VERSION 5.7 ;
BUSBITCHARS "[]" ;
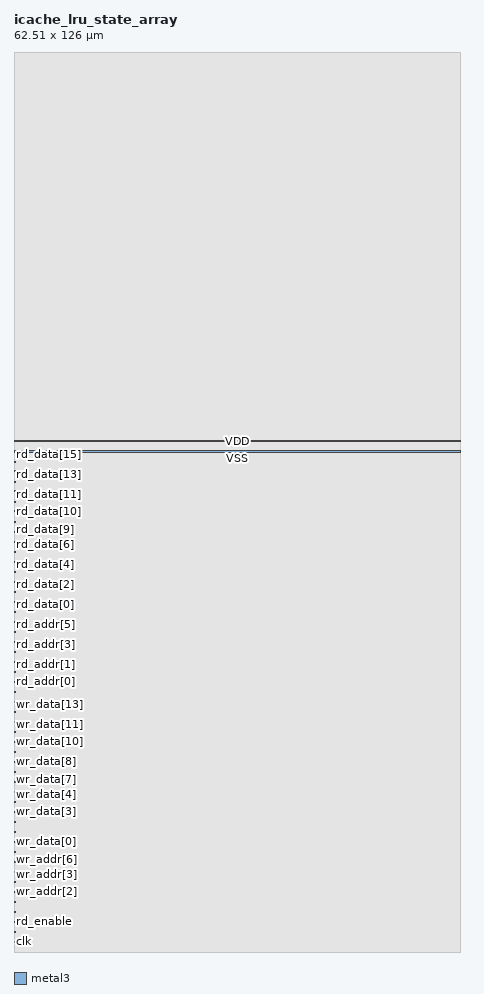
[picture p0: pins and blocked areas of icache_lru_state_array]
MACRO icache_lru_state_array
  FOREIGN icache_lru_state_array 0 0 ;
  SYMMETRY X Y R90 ;
  SIZE 62.510 BY 126.000 ;
  CLASS BLOCK ;
  PIN clk
    DIRECTION INPUT ;
    USE SIGNAL ;
    SHAPE ABUTMENT ;
    PORT
      LAYER metal3 ;
      RECT 0.000 1.400 0.140 1.540 ;
    END
  END clk
  PIN wr_enable
    DIRECTION INPUT ;
    USE SIGNAL ;
    SHAPE ABUTMENT ;
    PORT
      LAYER metal3 ;
      RECT 0.000 2.800 0.140 2.940 ;
    END
  END wr_enable
  PIN rd_enable
    DIRECTION INPUT ;
    USE SIGNAL ;
    SHAPE ABUTMENT ;
    PORT
      LAYER metal3 ;
      RECT 0.000 4.200 0.140 4.340 ;
    END
  END rd_enable
  PIN wr_addr[0]
    DIRECTION INPUT ;
    USE SIGNAL ;
    SHAPE ABUTMENT ;
    PORT
      LAYER metal3 ;
      RECT 0.000 5.600 0.140 5.740 ;
    END
  END wr_addr[0]
  PIN wr_addr[1]
    DIRECTION INPUT ;
    USE SIGNAL ;
    SHAPE ABUTMENT ;
    PORT
      LAYER metal3 ;
      RECT 0.000 7.000 0.140 7.140 ;
    END
  END wr_addr[1]
  PIN wr_addr[2]
    DIRECTION INPUT ;
    USE SIGNAL ;
    SHAPE ABUTMENT ;
    PORT
      LAYER metal3 ;
      RECT 0.000 8.400 0.140 8.540 ;
    END
  END wr_addr[2]
  PIN wr_addr[3]
    DIRECTION INPUT ;
    USE SIGNAL ;
    SHAPE ABUTMENT ;
    PORT
      LAYER metal3 ;
      RECT 0.000 9.800 0.140 9.940 ;
    END
  END wr_addr[3]
  PIN wr_addr[4]
    DIRECTION INPUT ;
    USE SIGNAL ;
    SHAPE ABUTMENT ;
    PORT
      LAYER metal3 ;
      RECT 0.000 11.200 0.140 11.340 ;
    END
  END wr_addr[4]
  PIN wr_addr[5]
    DIRECTION INPUT ;
    USE SIGNAL ;
    SHAPE ABUTMENT ;
    PORT
      LAYER metal3 ;
      RECT 0.000 12.600 0.140 12.740 ;
    END
  END wr_addr[5]
  PIN wr_addr[6]
    DIRECTION INPUT ;
    USE SIGNAL ;
    SHAPE ABUTMENT ;
    PORT
      LAYER metal3 ;
      RECT 0.000 14.000 0.140 14.140 ;
    END
  END wr_addr[6]
  PIN wr_data[0]
    DIRECTION INPUT ;
    USE SIGNAL ;
    SHAPE ABUTMENT ;
    PORT
      LAYER metal3 ;
      RECT 0.000 15.400 0.140 15.540 ;
    END
  END wr_data[0]
  PIN wr_data[1]
    DIRECTION INPUT ;
    USE SIGNAL ;
    SHAPE ABUTMENT ;
    PORT
      LAYER metal3 ;
      RECT 0.000 16.800 0.140 16.940 ;
    END
  END wr_data[1]
  PIN wr_data[2]
    DIRECTION INPUT ;
    USE SIGNAL ;
    SHAPE ABUTMENT ;
    PORT
      LAYER metal3 ;
      RECT 0.000 18.200 0.140 18.340 ;
    END
  END wr_data[2]
  PIN wr_data[3]
    DIRECTION INPUT ;
    USE SIGNAL ;
    SHAPE ABUTMENT ;
    PORT
      LAYER metal3 ;
      RECT 0.000 19.600 0.140 19.740 ;
    END
  END wr_data[3]
  PIN wr_data[4]
    DIRECTION INPUT ;
    USE SIGNAL ;
    SHAPE ABUTMENT ;
    PORT
      LAYER metal3 ;
      RECT 0.000 21.000 0.140 21.140 ;
    END
  END wr_data[4]
  PIN wr_data[5]
    DIRECTION INPUT ;
    USE SIGNAL ;
    SHAPE ABUTMENT ;
    PORT
      LAYER metal3 ;
      RECT 0.000 22.400 0.140 22.540 ;
    END
  END wr_data[5]
  PIN wr_data[6]
    DIRECTION INPUT ;
    USE SIGNAL ;
    SHAPE ABUTMENT ;
    PORT
      LAYER metal3 ;
      RECT 0.000 23.800 0.140 23.940 ;
    END
  END wr_data[6]
  PIN wr_data[7]
    DIRECTION INPUT ;
    USE SIGNAL ;
    SHAPE ABUTMENT ;
    PORT
      LAYER metal3 ;
      RECT 0.000 25.200 0.140 25.340 ;
    END
  END wr_data[7]
  PIN wr_data[8]
    DIRECTION INPUT ;
    USE SIGNAL ;
    SHAPE ABUTMENT ;
    PORT
      LAYER metal3 ;
      RECT 0.000 26.600 0.140 26.740 ;
    END
  END wr_data[8]
  PIN wr_data[9]
    DIRECTION INPUT ;
    USE SIGNAL ;
    SHAPE ABUTMENT ;
    PORT
      LAYER metal3 ;
      RECT 0.000 28.000 0.140 28.140 ;
    END
  END wr_data[9]
  PIN wr_data[10]
    DIRECTION INPUT ;
    USE SIGNAL ;
    SHAPE ABUTMENT ;
    PORT
      LAYER metal3 ;
      RECT 0.000 29.400 0.140 29.540 ;
    END
  END wr_data[10]
  PIN wr_data[11]
    DIRECTION INPUT ;
    USE SIGNAL ;
    SHAPE ABUTMENT ;
    PORT
      LAYER metal3 ;
      RECT 0.000 30.800 0.140 30.940 ;
    END
  END wr_data[11]
  PIN wr_data[12]
    DIRECTION INPUT ;
    USE SIGNAL ;
    SHAPE ABUTMENT ;
    PORT
      LAYER metal3 ;
      RECT 0.000 32.200 0.140 32.340 ;
    END
  END wr_data[12]
  PIN wr_data[13]
    DIRECTION INPUT ;
    USE SIGNAL ;
    SHAPE ABUTMENT ;
    PORT
      LAYER metal3 ;
      RECT 0.000 33.600 0.140 33.740 ;
    END
  END wr_data[13]
  PIN wr_data[14]
    DIRECTION INPUT ;
    USE SIGNAL ;
    SHAPE ABUTMENT ;
    PORT
      LAYER metal3 ;
      RECT 0.000 35.000 0.140 35.140 ;
    END
  END wr_data[14]
  PIN wr_data[15]
    DIRECTION INPUT ;
    USE SIGNAL ;
    SHAPE ABUTMENT ;
    PORT
      LAYER metal3 ;
      RECT 0.000 36.400 0.140 36.540 ;
    END
  END wr_data[15]
  PIN rd_addr[0]
    DIRECTION INPUT ;
    USE SIGNAL ;
    SHAPE ABUTMENT ;
    PORT
      LAYER metal3 ;
      RECT 0.000 37.800 0.140 37.940 ;
    END
  END rd_addr[0]
  PIN rd_addr[1]
    DIRECTION INPUT ;
    USE SIGNAL ;
    SHAPE ABUTMENT ;
    PORT
      LAYER metal3 ;
      RECT 0.000 39.200 0.140 39.340 ;
    END
  END rd_addr[1]
  PIN rd_addr[2]
    DIRECTION INPUT ;
    USE SIGNAL ;
    SHAPE ABUTMENT ;
    PORT
      LAYER metal3 ;
      RECT 0.000 40.600 0.140 40.740 ;
    END
  END rd_addr[2]
  PIN rd_addr[3]
    DIRECTION INPUT ;
    USE SIGNAL ;
    SHAPE ABUTMENT ;
    PORT
      LAYER metal3 ;
      RECT 0.000 42.000 0.140 42.140 ;
    END
  END rd_addr[3]
  PIN rd_addr[4]
    DIRECTION INPUT ;
    USE SIGNAL ;
    SHAPE ABUTMENT ;
    PORT
      LAYER metal3 ;
      RECT 0.000 43.400 0.140 43.540 ;
    END
  END rd_addr[4]
  PIN rd_addr[5]
    DIRECTION INPUT ;
    USE SIGNAL ;
    SHAPE ABUTMENT ;
    PORT
      LAYER metal3 ;
      RECT 0.000 44.800 0.140 44.940 ;
    END
  END rd_addr[5]
  PIN rd_addr[6]
    DIRECTION INPUT ;
    USE SIGNAL ;
    SHAPE ABUTMENT ;
    PORT
      LAYER metal3 ;
      RECT 0.000 46.200 0.140 46.340 ;
    END
  END rd_addr[6]
  PIN rd_data[0]
    DIRECTION OUTPUT ;
    USE SIGNAL ;
    SHAPE ABUTMENT ;
    PORT
      LAYER metal3 ;
      RECT 0.000 47.600 0.140 47.740 ;
    END
  END rd_data[0]
  PIN rd_data[1]
    DIRECTION OUTPUT ;
    USE SIGNAL ;
    SHAPE ABUTMENT ;
    PORT
      LAYER metal3 ;
      RECT 0.000 49.000 0.140 49.140 ;
    END
  END rd_data[1]
  PIN rd_data[2]
    DIRECTION OUTPUT ;
    USE SIGNAL ;
    SHAPE ABUTMENT ;
    PORT
      LAYER metal3 ;
      RECT 0.000 50.400 0.140 50.540 ;
    END
  END rd_data[2]
  PIN rd_data[3]
    DIRECTION OUTPUT ;
    USE SIGNAL ;
    SHAPE ABUTMENT ;
    PORT
      LAYER metal3 ;
      RECT 0.000 51.800 0.140 51.940 ;
    END
  END rd_data[3]
  PIN rd_data[4]
    DIRECTION OUTPUT ;
    USE SIGNAL ;
    SHAPE ABUTMENT ;
    PORT
      LAYER metal3 ;
      RECT 0.000 53.200 0.140 53.340 ;
    END
  END rd_data[4]
  PIN rd_data[5]
    DIRECTION OUTPUT ;
    USE SIGNAL ;
    SHAPE ABUTMENT ;
    PORT
      LAYER metal3 ;
      RECT 0.000 54.600 0.140 54.740 ;
    END
  END rd_data[5]
  PIN rd_data[6]
    DIRECTION OUTPUT ;
    USE SIGNAL ;
    SHAPE ABUTMENT ;
    PORT
      LAYER metal3 ;
      RECT 0.000 56.000 0.140 56.140 ;
    END
  END rd_data[6]
  PIN rd_data[7]
    DIRECTION OUTPUT ;
    USE SIGNAL ;
    SHAPE ABUTMENT ;
    PORT
      LAYER metal3 ;
      RECT 0.000 57.400 0.140 57.540 ;
    END
  END rd_data[7]
  PIN rd_data[8]
    DIRECTION OUTPUT ;
    USE SIGNAL ;
    SHAPE ABUTMENT ;
    PORT
      LAYER metal3 ;
      RECT 0.000 58.800 0.140 58.940 ;
    END
  END rd_data[8]
  PIN rd_data[9]
    DIRECTION OUTPUT ;
    USE SIGNAL ;
    SHAPE ABUTMENT ;
    PORT
      LAYER metal3 ;
      RECT 0.000 60.200 0.140 60.340 ;
    END
  END rd_data[9]
  PIN rd_data[10]
    DIRECTION OUTPUT ;
    USE SIGNAL ;
    SHAPE ABUTMENT ;
    PORT
      LAYER metal3 ;
      RECT 0.000 61.600 0.140 61.740 ;
    END
  END rd_data[10]
  PIN rd_data[11]
    DIRECTION OUTPUT ;
    USE SIGNAL ;
    SHAPE ABUTMENT ;
    PORT
      LAYER metal3 ;
      RECT 0.000 63.000 0.140 63.140 ;
    END
  END rd_data[11]
  PIN rd_data[12]
    DIRECTION OUTPUT ;
    USE SIGNAL ;
    SHAPE ABUTMENT ;
    PORT
      LAYER metal3 ;
      RECT 0.000 64.400 0.140 64.540 ;
    END
  END rd_data[12]
  PIN rd_data[13]
    DIRECTION OUTPUT ;
    USE SIGNAL ;
    SHAPE ABUTMENT ;
    PORT
      LAYER metal3 ;
      RECT 0.000 65.800 0.140 65.940 ;
    END
  END rd_data[13]
  PIN rd_data[14]
    DIRECTION OUTPUT ;
    USE SIGNAL ;
    SHAPE ABUTMENT ;
    PORT
      LAYER metal3 ;
      RECT 0.000 67.200 0.140 67.340 ;
    END
  END rd_data[14]
  PIN rd_data[15]
    DIRECTION OUTPUT ;
    USE SIGNAL ;
    SHAPE ABUTMENT ;
    PORT
      LAYER metal3 ;
      RECT 0.000 68.600 0.140 68.740 ;
    END
  END rd_data[15]
  PIN VSS
    DIRECTION INOUT ;
    USE GROUND ;
    SHAPE ABUTMENT ;
    PORT
      LAYER metal3 ;
      RECT 0.000 70.000 62.510 70.140 ;
    END
  END VSS
  PIN VDD
    DIRECTION INOUT ;
    USE POWER ;
    SHAPE ABUTMENT ;
    PORT
      LAYER metal3 ;
      RECT 0.000 71.400 62.510 71.540 ;
    END
  END VDD
  OBS
    LAYER metal1 ;
      RECT 0.000 0.000 62.510 126.000 ;
    LAYER metal2 ;
      RECT 0.000 0.000 62.510 126.000 ;
    LAYER metal3 ;
      RECT 0.000 0.000 62.510 126.000 ;
    LAYER metal4 ;
      RECT 0.000 0.000 62.510 126.000 ;
  END
END icache_lru_state_array
END LIBRARY
